VERSION 5.7 ;
  NOWIREEXTENSIONATPIN ON ;
  DIVIDERCHAR "/" ;
  BUSBITCHARS "[]" ;
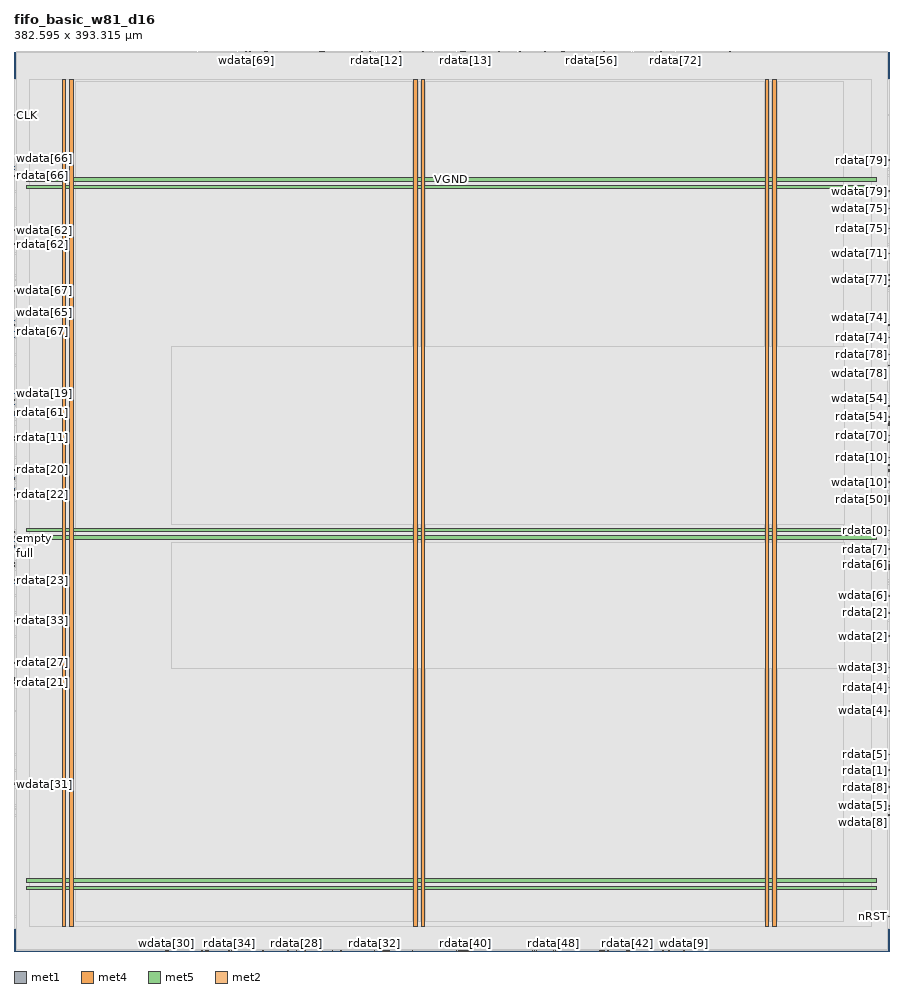
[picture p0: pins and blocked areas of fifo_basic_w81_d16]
MACRO fifo_basic_w81_d16
  CLASS BLOCK ;
  FOREIGN fifo_basic_w81_d16 ;
  ORIGIN 0.000 0.000 ;
  SIZE 382.595 BY 393.315 ;
  PIN CLK
    DIRECTION INPUT ;
    USE SIGNAL ;
    ANTENNAGATEAREA 0.852000 ;
    PORT
      LAYER met1 ;
        RECT 0.000 365.190 0.300 365.470 ;
    END
  END CLK
  PIN VGND
    DIRECTION INOUT ;
    USE GROUND ;
    PORT
      LAYER met4 ;
        RECT 24.340 10.640 25.940 381.040 ;
    END
    PORT
      LAYER met4 ;
        RECT 177.940 10.640 179.540 381.040 ;
    END
    PORT
      LAYER met4 ;
        RECT 331.540 10.640 333.140 381.040 ;
    END
    PORT
      LAYER met5 ;
        RECT 5.520 30.030 376.740 31.630 ;
    END
    PORT
      LAYER met5 ;
        RECT 5.520 183.210 376.740 184.810 ;
    END
    PORT
      LAYER met5 ;
        RECT 5.520 336.390 376.740 337.990 ;
    END
  END VGND
  PIN VPWR
    DIRECTION INOUT ;
    USE POWER ;
    PORT
      LAYER met4 ;
        RECT 21.040 10.640 22.640 381.040 ;
    END
    PORT
      LAYER met4 ;
        RECT 174.640 10.640 176.240 381.040 ;
    END
    PORT
      LAYER met4 ;
        RECT 328.240 10.640 329.840 381.040 ;
    END
    PORT
      LAYER met5 ;
        RECT 5.520 26.730 376.740 28.330 ;
    END
    PORT
      LAYER met5 ;
        RECT 5.520 179.910 376.740 181.510 ;
    END
    PORT
      LAYER met5 ;
        RECT 5.520 333.090 376.740 334.690 ;
    END
  END VPWR
  PIN empty
    DIRECTION OUTPUT ;
    USE SIGNAL ;
    ANTENNADIFFAREA 0.702900 ;
    PORT
      LAYER met1 ;
        RECT 0.000 180.230 0.300 180.510 ;
    END
  END empty
  PIN full
    DIRECTION OUTPUT ;
    USE SIGNAL ;
    ANTENNADIFFAREA 0.702900 ;
    PORT
      LAYER met1 ;
        RECT 0.000 176.830 0.300 177.110 ;
    END
  END full
  PIN nRST
    DIRECTION INPUT ;
    USE SIGNAL ;
    ANTENNAGATEAREA 0.196500 ;
    PORT
      LAYER met1 ;
        RECT 382.295 14.990 382.595 15.270 ;
    END
  END nRST
  PIN rdata[0]
    DIRECTION OUTPUT ;
    USE SIGNAL ;
    ANTENNADIFFAREA 0.702900 ;
    PORT
      LAYER met1 ;
        RECT 382.295 183.630 382.595 183.910 ;
    END
  END rdata[0]
  PIN rdata[10]
    DIRECTION OUTPUT ;
    USE SIGNAL ;
    ANTENNADIFFAREA 0.702900 ;
    PORT
      LAYER met1 ;
        RECT 382.295 215.590 382.595 215.870 ;
    END
  END rdata[10]
  PIN rdata[11]
    DIRECTION OUTPUT ;
    USE SIGNAL ;
    ANTENNADIFFAREA 0.702900 ;
    PORT
      LAYER met1 ;
        RECT 0.000 224.430 0.300 224.710 ;
    END
  END rdata[11]
  PIN rdata[12]
    DIRECTION OUTPUT ;
    USE SIGNAL ;
    ANTENNADIFFAREA 0.702900 ;
    PORT
      LAYER met2 ;
        RECT 158.330 393.035 158.610 393.315 ;
    END
  END rdata[12]
  PIN rdata[13]
    DIRECTION OUTPUT ;
    USE SIGNAL ;
    ANTENNADIFFAREA 0.702900 ;
    PORT
      LAYER met2 ;
        RECT 196.970 393.035 197.250 393.315 ;
    END
  END rdata[13]
  PIN rdata[14]
    DIRECTION OUTPUT ;
    USE SIGNAL ;
    ANTENNADIFFAREA 0.702900 ;
    PORT
      LAYER met2 ;
        RECT 193.290 393.035 193.570 393.315 ;
    END
  END rdata[14]
  PIN rdata[15]
    DIRECTION OUTPUT ;
    USE SIGNAL ;
    ANTENNADIFFAREA 0.702900 ;
    PORT
      LAYER met2 ;
        RECT 135.330 393.035 135.610 393.315 ;
    END
  END rdata[15]
  PIN rdata[16]
    DIRECTION OUTPUT ;
    USE SIGNAL ;
    ANTENNADIFFAREA 0.702900 ;
    PORT
      LAYER met2 ;
        RECT 134.410 393.035 134.690 393.315 ;
    END
  END rdata[16]
  PIN rdata[17]
    DIRECTION OUTPUT ;
    USE SIGNAL ;
    ANTENNADIFFAREA 0.702900 ;
    PORT
      LAYER met2 ;
        RECT 151.890 393.035 152.170 393.315 ;
    END
  END rdata[17]
  PIN rdata[18]
    DIRECTION OUTPUT ;
    USE SIGNAL ;
    ANTENNADIFFAREA 0.702900 ;
    PORT
      LAYER met2 ;
        RECT 178.570 393.035 178.850 393.315 ;
    END
  END rdata[18]
  PIN rdata[19]
    DIRECTION OUTPUT ;
    USE SIGNAL ;
    ANTENNADIFFAREA 0.702900 ;
    PORT
      LAYER met1 ;
        RECT 0.000 223.070 0.300 223.350 ;
    END
  END rdata[19]
  PIN rdata[1]
    DIRECTION OUTPUT ;
    USE SIGNAL ;
    ANTENNADIFFAREA 0.702900 ;
    PORT
      LAYER met1 ;
        RECT 382.295 78.910 382.595 79.190 ;
    END
  END rdata[1]
  PIN rdata[20]
    DIRECTION OUTPUT ;
    USE SIGNAL ;
    ANTENNADIFFAREA 0.702900 ;
    PORT
      LAYER met1 ;
        RECT 0.000 210.150 0.300 210.430 ;
    END
  END rdata[20]
  PIN rdata[21]
    DIRECTION OUTPUT ;
    USE SIGNAL ;
    ANTENNADIFFAREA 0.702900 ;
    PORT
      LAYER met1 ;
        RECT 0.000 116.990 0.300 117.270 ;
    END
  END rdata[21]
  PIN rdata[22]
    DIRECTION OUTPUT ;
    USE SIGNAL ;
    ANTENNADIFFAREA 0.702900 ;
    PORT
      LAYER met1 ;
        RECT 0.000 199.270 0.300 199.550 ;
    END
  END rdata[22]
  PIN rdata[23]
    DIRECTION OUTPUT ;
    USE SIGNAL ;
    ANTENNADIFFAREA 0.702900 ;
    PORT
      LAYER met1 ;
        RECT 0.000 161.870 0.300 162.150 ;
    END
  END rdata[23]
  PIN rdata[24]
    DIRECTION OUTPUT ;
    USE SIGNAL ;
    ANTENNADIFFAREA 0.702900 ;
    PORT
      LAYER met2 ;
        RECT 83.810 0.000 84.090 0.280 ;
    END
  END rdata[24]
  PIN rdata[25]
    DIRECTION OUTPUT ;
    USE SIGNAL ;
    ANTENNADIFFAREA 0.702900 ;
    PORT
      LAYER met1 ;
        RECT 0.000 169.350 0.300 169.630 ;
    END
  END rdata[25]
  PIN rdata[26]
    DIRECTION OUTPUT ;
    USE SIGNAL ;
    ANTENNADIFFAREA 0.702900 ;
    PORT
      LAYER met1 ;
        RECT 0.000 201.990 0.300 202.270 ;
    END
  END rdata[26]
  PIN rdata[27]
    DIRECTION OUTPUT ;
    USE SIGNAL ;
    ANTENNADIFFAREA 0.702900 ;
    PORT
      LAYER met1 ;
        RECT 0.000 125.830 0.300 126.110 ;
    END
  END rdata[27]
  PIN rdata[28]
    DIRECTION OUTPUT ;
    USE SIGNAL ;
    ANTENNADIFFAREA 0.702900 ;
    PORT
      LAYER met2 ;
        RECT 123.370 0.000 123.650 0.280 ;
    END
  END rdata[28]
  PIN rdata[29]
    DIRECTION OUTPUT ;
    USE SIGNAL ;
    ANTENNADIFFAREA 0.702900 ;
    PORT
      LAYER met1 ;
        RECT 0.000 178.870 0.300 179.150 ;
    END
  END rdata[29]
  PIN rdata[2]
    DIRECTION OUTPUT ;
    USE SIGNAL ;
    ANTENNADIFFAREA 0.702900 ;
    PORT
      LAYER met1 ;
        RECT 382.295 147.590 382.595 147.870 ;
    END
  END rdata[2]
  PIN rdata[30]
    DIRECTION OUTPUT ;
    USE SIGNAL ;
    ANTENNADIFFAREA 0.702900 ;
    PORT
      LAYER met2 ;
        RECT 84.730 0.000 85.010 0.280 ;
    END
  END rdata[30]
  PIN rdata[31]
    DIRECTION OUTPUT ;
    USE SIGNAL ;
    ANTENNADIFFAREA 0.702900 ;
    PORT
      LAYER met1 ;
        RECT 0.000 73.470 0.300 73.750 ;
    END
  END rdata[31]
  PIN rdata[32]
    DIRECTION OUTPUT ;
    USE SIGNAL ;
    ANTENNADIFFAREA 0.702900 ;
    PORT
      LAYER met2 ;
        RECT 157.410 0.000 157.690 0.280 ;
    END
  END rdata[32]
  PIN rdata[33]
    DIRECTION OUTPUT ;
    USE SIGNAL ;
    ANTENNADIFFAREA 0.702900 ;
    PORT
      LAYER met1 ;
        RECT 0.000 144.190 0.300 144.470 ;
    END
  END rdata[33]
  PIN rdata[34]
    DIRECTION OUTPUT ;
    USE SIGNAL ;
    ANTENNADIFFAREA 0.702900 ;
    PORT
      LAYER met2 ;
        RECT 93.930 0.000 94.210 0.280 ;
    END
  END rdata[34]
  PIN rdata[35]
    DIRECTION OUTPUT ;
    USE SIGNAL ;
    ANTENNADIFFAREA 0.702900 ;
    PORT
      LAYER met2 ;
        RECT 142.690 0.000 142.970 0.280 ;
    END
  END rdata[35]
  PIN rdata[36]
    DIRECTION OUTPUT ;
    USE SIGNAL ;
    ANTENNADIFFAREA 0.702900 ;
    PORT
      LAYER met2 ;
        RECT 127.050 0.000 127.330 0.280 ;
    END
  END rdata[36]
  PIN rdata[37]
    DIRECTION OUTPUT ;
    USE SIGNAL ;
    ANTENNADIFFAREA 0.702900 ;
    PORT
      LAYER met2 ;
        RECT 108.650 0.000 108.930 0.280 ;
    END
  END rdata[37]
  PIN rdata[38]
    DIRECTION OUTPUT ;
    USE SIGNAL ;
    ANTENNADIFFAREA 0.702900 ;
    PORT
      LAYER met2 ;
        RECT 161.090 0.000 161.370 0.280 ;
    END
  END rdata[38]
  PIN rdata[39]
    DIRECTION OUTPUT ;
    USE SIGNAL ;
    ANTENNADIFFAREA 0.702900 ;
    PORT
      LAYER met2 ;
        RECT 173.970 0.000 174.250 0.280 ;
    END
  END rdata[39]
  PIN rdata[3]
    DIRECTION OUTPUT ;
    USE SIGNAL ;
    ANTENNADIFFAREA 0.702900 ;
    PORT
      LAYER met2 ;
        RECT 283.450 0.000 283.730 0.280 ;
    END
  END rdata[3]
  PIN rdata[40]
    DIRECTION OUTPUT ;
    USE SIGNAL ;
    ANTENNADIFFAREA 0.702900 ;
    PORT
      LAYER met2 ;
        RECT 196.970 0.000 197.250 0.280 ;
    END
  END rdata[40]
  PIN rdata[41]
    DIRECTION OUTPUT ;
    USE SIGNAL ;
    ANTENNADIFFAREA 0.702900 ;
    PORT
      LAYER met2 ;
        RECT 193.290 0.000 193.570 0.280 ;
    END
  END rdata[41]
  PIN rdata[42]
    DIRECTION OUTPUT ;
    USE SIGNAL ;
    ANTENNADIFFAREA 0.702900 ;
    PORT
      LAYER met2 ;
        RECT 267.810 0.000 268.090 0.280 ;
    END
  END rdata[42]
  PIN rdata[43]
    DIRECTION OUTPUT ;
    USE SIGNAL ;
    ANTENNADIFFAREA 0.702900 ;
    PORT
      LAYER met2 ;
        RECT 237.450 0.000 237.730 0.280 ;
    END
  END rdata[43]
  PIN rdata[44]
    DIRECTION OUTPUT ;
    USE SIGNAL ;
    ANTENNADIFFAREA 0.702900 ;
    PORT
      LAYER met2 ;
        RECT 199.730 0.000 200.010 0.280 ;
    END
  END rdata[44]
  PIN rdata[45]
    DIRECTION OUTPUT ;
    USE SIGNAL ;
    ANTENNADIFFAREA 0.702900 ;
    PORT
      LAYER met2 ;
        RECT 259.530 0.000 259.810 0.280 ;
    END
  END rdata[45]
  PIN rdata[46]
    DIRECTION OUTPUT ;
    USE SIGNAL ;
    ANTENNADIFFAREA 0.702900 ;
    PORT
      LAYER met2 ;
        RECT 195.130 0.000 195.410 0.280 ;
    END
  END rdata[46]
  PIN rdata[47]
    DIRECTION OUTPUT ;
    USE SIGNAL ;
    ANTENNADIFFAREA 0.702900 ;
    PORT
      LAYER met2 ;
        RECT 226.410 0.000 226.690 0.280 ;
    END
  END rdata[47]
  PIN rdata[48]
    DIRECTION OUTPUT ;
    USE SIGNAL ;
    ANTENNADIFFAREA 0.702900 ;
    PORT
      LAYER met2 ;
        RECT 235.610 0.000 235.890 0.280 ;
    END
  END rdata[48]
  PIN rdata[49]
    DIRECTION OUTPUT ;
    USE SIGNAL ;
    ANTENNADIFFAREA 0.702900 ;
    PORT
      LAYER met2 ;
        RECT 268.730 0.000 269.010 0.280 ;
    END
  END rdata[49]
  PIN rdata[4]
    DIRECTION OUTPUT ;
    USE SIGNAL ;
    ANTENNADIFFAREA 0.702900 ;
    PORT
      LAYER met1 ;
        RECT 382.295 114.950 382.595 115.230 ;
    END
  END rdata[4]
  PIN rdata[50]
    DIRECTION OUTPUT ;
    USE SIGNAL ;
    ANTENNADIFFAREA 0.702900 ;
    PORT
      LAYER met1 ;
        RECT 382.295 197.230 382.595 197.510 ;
    END
  END rdata[50]
  PIN rdata[51]
    DIRECTION OUTPUT ;
    USE SIGNAL ;
    ANTENNADIFFAREA 0.702900 ;
    PORT
      LAYER met1 ;
        RECT 382.295 196.550 382.595 196.830 ;
    END
  END rdata[51]
  PIN rdata[52]
    DIRECTION OUTPUT ;
    USE SIGNAL ;
    ANTENNADIFFAREA 0.702900 ;
    PORT
      LAYER met2 ;
        RECT 219.970 393.035 220.250 393.315 ;
    END
  END rdata[52]
  PIN rdata[53]
    DIRECTION OUTPUT ;
    USE SIGNAL ;
    ANTENNADIFFAREA 0.702900 ;
    PORT
      LAYER met2 ;
        RECT 269.650 393.035 269.930 393.315 ;
    END
  END rdata[53]
  PIN rdata[54]
    DIRECTION OUTPUT ;
    USE SIGNAL ;
    ANTENNADIFFAREA 0.702900 ;
    PORT
      LAYER met1 ;
        RECT 382.295 233.270 382.595 233.550 ;
    END
  END rdata[54]
  PIN rdata[55]
    DIRECTION OUTPUT ;
    USE SIGNAL ;
    ANTENNADIFFAREA 0.702900 ;
    PORT
      LAYER met2 ;
        RECT 270.570 393.035 270.850 393.315 ;
    END
  END rdata[55]
  PIN rdata[56]
    DIRECTION OUTPUT ;
    USE SIGNAL ;
    ANTENNADIFFAREA 0.702900 ;
    PORT
      LAYER met2 ;
        RECT 252.170 393.035 252.450 393.315 ;
    END
  END rdata[56]
  PIN rdata[57]
    DIRECTION OUTPUT ;
    USE SIGNAL ;
    ANTENNADIFFAREA 0.702900 ;
    PORT
      LAYER met2 ;
        RECT 231.930 393.035 232.210 393.315 ;
    END
  END rdata[57]
  PIN rdata[58]
    DIRECTION OUTPUT ;
    USE SIGNAL ;
    ANTENNADIFFAREA 0.702900 ;
    PORT
      LAYER met1 ;
        RECT 382.295 231.230 382.595 231.510 ;
    END
  END rdata[58]
  PIN rdata[59]
    DIRECTION OUTPUT ;
    USE SIGNAL ;
    ANTENNADIFFAREA 0.702900 ;
    PORT
      LAYER met2 ;
        RECT 211.690 393.035 211.970 393.315 ;
    END
  END rdata[59]
  PIN rdata[5]
    DIRECTION OUTPUT ;
    USE SIGNAL ;
    ANTENNADIFFAREA 0.702900 ;
    PORT
      LAYER met1 ;
        RECT 382.295 85.710 382.595 85.990 ;
    END
  END rdata[5]
  PIN rdata[60]
    DIRECTION OUTPUT ;
    USE SIGNAL ;
    ANTENNADIFFAREA 0.702900 ;
    PORT
      LAYER met2 ;
        RECT 109.570 393.035 109.850 393.315 ;
    END
  END rdata[60]
  PIN rdata[61]
    DIRECTION OUTPUT ;
    USE SIGNAL ;
    ANTENNADIFFAREA 0.702900 ;
    PORT
      LAYER met1 ;
        RECT 0.000 235.310 0.300 235.590 ;
    END
  END rdata[61]
  PIN rdata[62]
    DIRECTION OUTPUT ;
    USE SIGNAL ;
    ANTENNADIFFAREA 0.702900 ;
    PORT
      LAYER met1 ;
        RECT 0.000 308.750 0.300 309.030 ;
    END
  END rdata[62]
  PIN rdata[63]
    DIRECTION OUTPUT ;
    USE SIGNAL ;
    ANTENNADIFFAREA 0.702900 ;
    PORT
      LAYER met2 ;
        RECT 97.610 393.035 97.890 393.315 ;
    END
  END rdata[63]
  PIN rdata[64]
    DIRECTION OUTPUT ;
    USE SIGNAL ;
    ANTENNADIFFAREA 0.702900 ;
    PORT
      LAYER met2 ;
        RECT 80.130 393.035 80.410 393.315 ;
    END
  END rdata[64]
  PIN rdata[65]
    DIRECTION OUTPUT ;
    USE SIGNAL ;
    ANTENNADIFFAREA 0.702900 ;
    PORT
      LAYER met1 ;
        RECT 0.000 273.390 0.300 273.670 ;
    END
  END rdata[65]
  PIN rdata[66]
    DIRECTION OUTPUT ;
    USE SIGNAL ;
    ANTENNADIFFAREA 0.702900 ;
    PORT
      LAYER met1 ;
        RECT 0.000 338.670 0.300 338.950 ;
    END
  END rdata[66]
  PIN rdata[67]
    DIRECTION OUTPUT ;
    USE SIGNAL ;
    ANTENNADIFFAREA 0.702900 ;
    PORT
      LAYER met1 ;
        RECT 0.000 270.670 0.300 270.950 ;
    END
  END rdata[67]
  PIN rdata[68]
    DIRECTION OUTPUT ;
    USE SIGNAL ;
    ANTENNADIFFAREA 0.702900 ;
    PORT
      LAYER met1 ;
        RECT 0.000 234.630 0.300 234.910 ;
    END
  END rdata[68]
  PIN rdata[69]
    DIRECTION OUTPUT ;
    USE SIGNAL ;
    ANTENNADIFFAREA 0.702900 ;
    PORT
      LAYER met2 ;
        RECT 110.490 393.035 110.770 393.315 ;
    END
  END rdata[69]
  PIN rdata[6]
    DIRECTION OUTPUT ;
    USE SIGNAL ;
    ANTENNADIFFAREA 0.702900 ;
    PORT
      LAYER met1 ;
        RECT 382.295 168.670 382.595 168.950 ;
    END
  END rdata[6]
  PIN rdata[70]
    DIRECTION OUTPUT ;
    USE SIGNAL ;
    ANTENNADIFFAREA 0.702900 ;
    PORT
      LAYER met1 ;
        RECT 382.295 225.110 382.595 225.390 ;
    END
  END rdata[70]
  PIN rdata[71]
    DIRECTION OUTPUT ;
    USE SIGNAL ;
    ANTENNADIFFAREA 0.702900 ;
    PORT
      LAYER met1 ;
        RECT 382.295 295.150 382.595 295.430 ;
    END
  END rdata[71]
  PIN rdata[72]
    DIRECTION OUTPUT ;
    USE SIGNAL ;
    ANTENNADIFFAREA 0.702900 ;
    PORT
      LAYER met2 ;
        RECT 288.970 393.035 289.250 393.315 ;
    END
  END rdata[72]
  PIN rdata[73]
    DIRECTION OUTPUT ;
    USE SIGNAL ;
    ANTENNADIFFAREA 0.702900 ;
    PORT
      LAYER met1 ;
        RECT 382.295 222.390 382.595 222.670 ;
    END
  END rdata[73]
  PIN rdata[74]
    DIRECTION OUTPUT ;
    USE SIGNAL ;
    ANTENNADIFFAREA 0.702900 ;
    PORT
      LAYER met1 ;
        RECT 382.295 267.950 382.595 268.230 ;
    END
  END rdata[74]
  PIN rdata[75]
    DIRECTION OUTPUT ;
    USE SIGNAL ;
    ANTENNADIFFAREA 0.702900 ;
    PORT
      LAYER met1 ;
        RECT 382.295 315.550 382.595 315.830 ;
    END
  END rdata[75]
  PIN rdata[76]
    DIRECTION OUTPUT ;
    USE SIGNAL ;
    ANTENNADIFFAREA 0.702900 ;
    PORT
      LAYER met1 ;
        RECT 382.295 229.870 382.595 230.150 ;
    END
  END rdata[76]
  PIN rdata[77]
    DIRECTION OUTPUT ;
    USE SIGNAL ;
    ANTENNADIFFAREA 0.702900 ;
    PORT
      LAYER met1 ;
        RECT 382.295 290.390 382.595 290.670 ;
    END
  END rdata[77]
  PIN rdata[78]
    DIRECTION OUTPUT ;
    USE SIGNAL ;
    ANTENNADIFFAREA 0.702900 ;
    PORT
      LAYER met1 ;
        RECT 382.295 260.470 382.595 260.750 ;
    END
  END rdata[78]
  PIN rdata[79]
    DIRECTION OUTPUT ;
    USE SIGNAL ;
    ANTENNADIFFAREA 0.702900 ;
    PORT
      LAYER met1 ;
        RECT 382.295 345.470 382.595 345.750 ;
    END
  END rdata[79]
  PIN rdata[7]
    DIRECTION OUTPUT ;
    USE SIGNAL ;
    ANTENNADIFFAREA 0.702900 ;
    PORT
      LAYER met1 ;
        RECT 382.295 175.470 382.595 175.750 ;
    END
  END rdata[7]
  PIN rdata[80]
    DIRECTION OUTPUT ;
    USE SIGNAL ;
    ANTENNADIFFAREA 0.702900 ;
    PORT
      LAYER met1 ;
        RECT 382.295 170.030 382.595 170.310 ;
    END
  END rdata[80]
  PIN rdata[8]
    DIRECTION OUTPUT ;
    USE SIGNAL ;
    ANTENNADIFFAREA 0.702900 ;
    PORT
      LAYER met1 ;
        RECT 382.295 71.430 382.595 71.710 ;
    END
  END rdata[8]
  PIN rdata[9]
    DIRECTION OUTPUT ;
    USE SIGNAL ;
    ANTENNADIFFAREA 0.702900 ;
    PORT
      LAYER met2 ;
        RECT 286.210 0.000 286.490 0.280 ;
    END
  END rdata[9]
  PIN ren
    DIRECTION INPUT ;
    USE SIGNAL ;
    ANTENNAGATEAREA 0.213000 ;
    PORT
      LAYER met1 ;
        RECT 0.000 180.910 0.300 181.190 ;
    END
  END ren
  PIN wdata[0]
    DIRECTION INPUT ;
    USE SIGNAL ;
    ANTENNAGATEAREA 0.213000 ;
    PORT
      LAYER met1 ;
        RECT 382.295 166.630 382.595 166.910 ;
    END
  END wdata[0]
  PIN wdata[10]
    DIRECTION INPUT ;
    USE SIGNAL ;
    ANTENNAGATEAREA 0.213000 ;
    PORT
      LAYER met1 ;
        RECT 382.295 204.710 382.595 204.990 ;
    END
  END wdata[10]
  PIN wdata[11]
    DIRECTION INPUT ;
    USE SIGNAL ;
    ANTENNAGATEAREA 0.213000 ;
    PORT
      LAYER met1 ;
        RECT 0.000 233.950 0.300 234.230 ;
    END
  END wdata[11]
  PIN wdata[12]
    DIRECTION INPUT ;
    USE SIGNAL ;
    ANTENNAGATEAREA 0.213000 ;
    PORT
      LAYER met2 ;
        RECT 155.570 393.035 155.850 393.315 ;
    END
  END wdata[12]
  PIN wdata[13]
    DIRECTION INPUT ;
    USE SIGNAL ;
    ANTENNAGATEAREA 0.213000 ;
    PORT
      LAYER met2 ;
        RECT 196.050 393.035 196.330 393.315 ;
    END
  END wdata[13]
  PIN wdata[14]
    DIRECTION INPUT ;
    USE SIGNAL ;
    ANTENNAGATEAREA 0.213000 ;
    PORT
      LAYER met2 ;
        RECT 195.130 393.035 195.410 393.315 ;
    END
  END wdata[14]
  PIN wdata[15]
    DIRECTION INPUT ;
    USE SIGNAL ;
    ANTENNAGATEAREA 0.213000 ;
    PORT
      LAYER met2 ;
        RECT 133.490 393.035 133.770 393.315 ;
    END
  END wdata[15]
  PIN wdata[16]
    DIRECTION INPUT ;
    USE SIGNAL ;
    ANTENNAGATEAREA 0.213000 ;
    PORT
      LAYER met2 ;
        RECT 157.410 393.035 157.690 393.315 ;
    END
  END wdata[16]
  PIN wdata[17]
    DIRECTION INPUT ;
    USE SIGNAL ;
    ANTENNAGATEAREA 0.213000 ;
    PORT
      LAYER met2 ;
        RECT 168.450 393.035 168.730 393.315 ;
    END
  END wdata[17]
  PIN wdata[18]
    DIRECTION INPUT ;
    USE SIGNAL ;
    ANTENNAGATEAREA 0.213000 ;
    PORT
      LAYER met2 ;
        RECT 183.170 393.035 183.450 393.315 ;
    END
  END wdata[18]
  PIN wdata[19]
    DIRECTION INPUT ;
    USE SIGNAL ;
    ANTENNAGATEAREA 0.213000 ;
    PORT
      LAYER met1 ;
        RECT 0.000 243.470 0.300 243.750 ;
    END
  END wdata[19]
  PIN wdata[1]
    DIRECTION INPUT ;
    USE SIGNAL ;
    ANTENNAGATEAREA 0.213000 ;
    PORT
      LAYER met1 ;
        RECT 382.295 61.910 382.595 62.190 ;
    END
  END wdata[1]
  PIN wdata[20]
    DIRECTION INPUT ;
    USE SIGNAL ;
    ANTENNAGATEAREA 0.213000 ;
    PORT
      LAYER met1 ;
        RECT 0.000 206.750 0.300 207.030 ;
    END
  END wdata[20]
  PIN wdata[21]
    DIRECTION INPUT ;
    USE SIGNAL ;
    ANTENNAGATEAREA 0.213000 ;
    PORT
      LAYER met1 ;
        RECT 0.000 119.030 0.300 119.310 ;
    END
  END wdata[21]
  PIN wdata[22]
    DIRECTION INPUT ;
    USE SIGNAL ;
    ANTENNAGATEAREA 0.213000 ;
    PORT
      LAYER met1 ;
        RECT 0.000 206.070 0.300 206.350 ;
    END
  END wdata[22]
  PIN wdata[23]
    DIRECTION INPUT ;
    USE SIGNAL ;
    ANTENNAGATEAREA 0.213000 ;
    PORT
      LAYER met1 ;
        RECT 0.000 160.510 0.300 160.790 ;
    END
  END wdata[23]
  PIN wdata[24]
    DIRECTION INPUT ;
    USE SIGNAL ;
    ANTENNAGATEAREA 0.213000 ;
    PORT
      LAYER met2 ;
        RECT 81.970 0.000 82.250 0.280 ;
    END
  END wdata[24]
  PIN wdata[25]
    DIRECTION INPUT ;
    USE SIGNAL ;
    ANTENNAGATEAREA 0.213000 ;
    PORT
      LAYER met1 ;
        RECT 0.000 167.990 0.300 168.270 ;
    END
  END wdata[25]
  PIN wdata[26]
    DIRECTION INPUT ;
    USE SIGNAL ;
    ANTENNAGATEAREA 0.213000 ;
    PORT
      LAYER met1 ;
        RECT 0.000 201.310 0.300 201.590 ;
    END
  END wdata[26]
  PIN wdata[27]
    DIRECTION INPUT ;
    USE SIGNAL ;
    ANTENNAGATEAREA 0.213000 ;
    PORT
      LAYER met1 ;
        RECT 0.000 118.350 0.300 118.630 ;
    END
  END wdata[27]
  PIN wdata[28]
    DIRECTION INPUT ;
    USE SIGNAL ;
    ANTENNAGATEAREA 0.213000 ;
    PORT
      LAYER met2 ;
        RECT 94.850 0.000 95.130 0.280 ;
    END
  END wdata[28]
  PIN wdata[29]
    DIRECTION INPUT ;
    USE SIGNAL ;
    ANTENNAGATEAREA 0.213000 ;
    PORT
      LAYER met1 ;
        RECT 0.000 182.950 0.300 183.230 ;
    END
  END wdata[29]
  PIN wdata[2]
    DIRECTION INPUT ;
    USE SIGNAL ;
    ANTENNAGATEAREA 0.213000 ;
    PORT
      LAYER met1 ;
        RECT 382.295 137.390 382.595 137.670 ;
    END
  END wdata[2]
  PIN wdata[30]
    DIRECTION INPUT ;
    USE SIGNAL ;
    ANTENNAGATEAREA 0.213000 ;
    PORT
      LAYER met2 ;
        RECT 66.330 0.000 66.610 0.280 ;
    END
  END wdata[30]
  PIN wdata[31]
    DIRECTION INPUT ;
    USE SIGNAL ;
    ANTENNAGATEAREA 0.213000 ;
    PORT
      LAYER met1 ;
        RECT 0.000 72.790 0.300 73.070 ;
    END
  END wdata[31]
  PIN wdata[32]
    DIRECTION INPUT ;
    USE SIGNAL ;
    ANTENNAGATEAREA 0.213000 ;
    PORT
      LAYER met2 ;
        RECT 162.010 0.000 162.290 0.280 ;
    END
  END wdata[32]
  PIN wdata[33]
    DIRECTION INPUT ;
    USE SIGNAL ;
    ANTENNAGATEAREA 0.213000 ;
    PORT
      LAYER met2 ;
        RECT 134.410 0.000 134.690 0.280 ;
    END
  END wdata[33]
  PIN wdata[34]
    DIRECTION INPUT ;
    USE SIGNAL ;
    ANTENNAGATEAREA 0.213000 ;
    PORT
      LAYER met2 ;
        RECT 67.250 0.000 67.530 0.280 ;
    END
  END wdata[34]
  PIN wdata[35]
    DIRECTION INPUT ;
    USE SIGNAL ;
    ANTENNAGATEAREA 0.213000 ;
    PORT
      LAYER met2 ;
        RECT 139.010 0.000 139.290 0.280 ;
    END
  END wdata[35]
  PIN wdata[36]
    DIRECTION INPUT ;
    USE SIGNAL ;
    ANTENNAGATEAREA 0.213000 ;
    PORT
      LAYER met2 ;
        RECT 119.690 0.000 119.970 0.280 ;
    END
  END wdata[36]
  PIN wdata[37]
    DIRECTION INPUT ;
    USE SIGNAL ;
    ANTENNAGATEAREA 0.213000 ;
    PORT
      LAYER met2 ;
        RECT 95.770 0.000 96.050 0.280 ;
    END
  END wdata[37]
  PIN wdata[38]
    DIRECTION INPUT ;
    USE SIGNAL ;
    ANTENNAGATEAREA 0.213000 ;
    PORT
      LAYER met2 ;
        RECT 162.930 0.000 163.210 0.280 ;
    END
  END wdata[38]
  PIN wdata[39]
    DIRECTION INPUT ;
    USE SIGNAL ;
    ANTENNAGATEAREA 0.213000 ;
    PORT
      LAYER met2 ;
        RECT 163.850 0.000 164.130 0.280 ;
    END
  END wdata[39]
  PIN wdata[3]
    DIRECTION INPUT ;
    USE SIGNAL ;
    ANTENNAGATEAREA 0.213000 ;
    PORT
      LAYER met1 ;
        RECT 382.295 123.790 382.595 124.070 ;
    END
  END wdata[3]
  PIN wdata[40]
    DIRECTION INPUT ;
    USE SIGNAL ;
    ANTENNAGATEAREA 0.213000 ;
    PORT
      LAYER met2 ;
        RECT 194.210 0.000 194.490 0.280 ;
    END
  END wdata[40]
  PIN wdata[41]
    DIRECTION INPUT ;
    USE SIGNAL ;
    ANTENNAGATEAREA 0.213000 ;
    PORT
      LAYER met2 ;
        RECT 196.050 0.000 196.330 0.280 ;
    END
  END wdata[41]
  PIN wdata[42]
    DIRECTION INPUT ;
    USE SIGNAL ;
    ANTENNAGATEAREA 0.213000 ;
    PORT
      LAYER met2 ;
        RECT 256.770 0.000 257.050 0.280 ;
    END
  END wdata[42]
  PIN wdata[43]
    DIRECTION INPUT ;
    USE SIGNAL ;
    ANTENNAGATEAREA 0.213000 ;
    PORT
      LAYER met2 ;
        RECT 228.250 0.000 228.530 0.280 ;
    END
  END wdata[43]
  PIN wdata[44]
    DIRECTION INPUT ;
    USE SIGNAL ;
    ANTENNAGATEAREA 0.213000 ;
    PORT
      LAYER met2 ;
        RECT 197.890 0.000 198.170 0.280 ;
    END
  END wdata[44]
  PIN wdata[45]
    DIRECTION INPUT ;
    USE SIGNAL ;
    ANTENNAGATEAREA 0.213000 ;
    PORT
      LAYER met2 ;
        RECT 255.850 0.000 256.130 0.280 ;
    END
  END wdata[45]
  PIN wdata[46]
    DIRECTION INPUT ;
    USE SIGNAL ;
    ANTENNAGATEAREA 0.213000 ;
    PORT
      LAYER met2 ;
        RECT 198.810 0.000 199.090 0.280 ;
    END
  END wdata[46]
  PIN wdata[47]
    DIRECTION INPUT ;
    USE SIGNAL ;
    ANTENNAGATEAREA 0.213000 ;
    PORT
      LAYER met2 ;
        RECT 227.330 0.000 227.610 0.280 ;
    END
  END wdata[47]
  PIN wdata[48]
    DIRECTION INPUT ;
    USE SIGNAL ;
    ANTENNAGATEAREA 0.213000 ;
    PORT
      LAYER met2 ;
        RECT 236.530 0.000 236.810 0.280 ;
    END
  END wdata[48]
  PIN wdata[49]
    DIRECTION INPUT ;
    USE SIGNAL ;
    ANTENNAGATEAREA 0.213000 ;
    PORT
      LAYER met2 ;
        RECT 257.690 0.000 257.970 0.280 ;
    END
  END wdata[49]
  PIN wdata[4]
    DIRECTION INPUT ;
    USE SIGNAL ;
    ANTENNAGATEAREA 0.213000 ;
    PORT
      LAYER met1 ;
        RECT 382.295 104.750 382.595 105.030 ;
    END
  END wdata[4]
  PIN wdata[50]
    DIRECTION INPUT ;
    USE SIGNAL ;
    ANTENNAGATEAREA 0.213000 ;
    PORT
      LAYER met1 ;
        RECT 382.295 198.590 382.595 198.870 ;
    END
  END wdata[50]
  PIN wdata[51]
    DIRECTION INPUT ;
    USE SIGNAL ;
    ANTENNAGATEAREA 0.213000 ;
    PORT
      LAYER met1 ;
        RECT 382.295 197.910 382.595 198.190 ;
    END
  END wdata[51]
  PIN wdata[52]
    DIRECTION INPUT ;
    USE SIGNAL ;
    ANTENNAGATEAREA 0.213000 ;
    PORT
      LAYER met2 ;
        RECT 240.210 393.035 240.490 393.315 ;
    END
  END wdata[52]
  PIN wdata[53]
    DIRECTION INPUT ;
    USE SIGNAL ;
    ANTENNAGATEAREA 0.213000 ;
    PORT
      LAYER met2 ;
        RECT 282.530 393.035 282.810 393.315 ;
    END
  END wdata[53]
  PIN wdata[54]
    DIRECTION INPUT ;
    USE SIGNAL ;
    ANTENNAGATEAREA 0.213000 ;
    PORT
      LAYER met1 ;
        RECT 382.295 238.030 382.595 238.310 ;
    END
  END wdata[54]
  PIN wdata[55]
    DIRECTION INPUT ;
    USE SIGNAL ;
    ANTENNAGATEAREA 0.213000 ;
    PORT
      LAYER met2 ;
        RECT 279.770 393.035 280.050 393.315 ;
    END
  END wdata[55]
  PIN wdata[56]
    DIRECTION INPUT ;
    USE SIGNAL ;
    ANTENNAGATEAREA 0.213000 ;
    PORT
      LAYER met2 ;
        RECT 257.690 393.035 257.970 393.315 ;
    END
  END wdata[56]
  PIN wdata[57]
    DIRECTION INPUT ;
    USE SIGNAL ;
    ANTENNAGATEAREA 0.213000 ;
    PORT
      LAYER met2 ;
        RECT 239.290 393.035 239.570 393.315 ;
    END
  END wdata[57]
  PIN wdata[58]
    DIRECTION INPUT ;
    USE SIGNAL ;
    ANTENNAGATEAREA 0.213000 ;
    PORT
      LAYER met1 ;
        RECT 382.295 230.550 382.595 230.830 ;
    END
  END wdata[58]
  PIN wdata[59]
    DIRECTION INPUT ;
    USE SIGNAL ;
    ANTENNAGATEAREA 0.213000 ;
    PORT
      LAYER met2 ;
        RECT 220.890 393.035 221.170 393.315 ;
    END
  END wdata[59]
  PIN wdata[5]
    DIRECTION INPUT ;
    USE SIGNAL ;
    ANTENNAGATEAREA 0.213000 ;
    PORT
      LAYER met1 ;
        RECT 382.295 63.270 382.595 63.550 ;
    END
  END wdata[5]
  PIN wdata[60]
    DIRECTION INPUT ;
    USE SIGNAL ;
    ANTENNAGATEAREA 0.213000 ;
    PORT
      LAYER met2 ;
        RECT 103.130 393.035 103.410 393.315 ;
    END
  END wdata[60]
  PIN wdata[61]
    DIRECTION INPUT ;
    USE SIGNAL ;
    ANTENNAGATEAREA 0.213000 ;
    PORT
      LAYER met1 ;
        RECT 0.000 238.710 0.300 238.990 ;
    END
  END wdata[61]
  PIN wdata[62]
    DIRECTION INPUT ;
    USE SIGNAL ;
    ANTENNAGATEAREA 0.213000 ;
    PORT
      LAYER met1 ;
        RECT 0.000 314.870 0.300 315.150 ;
    END
  END wdata[62]
  PIN wdata[63]
    DIRECTION INPUT ;
    USE SIGNAL ;
    ANTENNAGATEAREA 0.213000 ;
    PORT
      LAYER met1 ;
        RECT 0.000 267.950 0.300 268.230 ;
    END
  END wdata[63]
  PIN wdata[64]
    DIRECTION INPUT ;
    USE SIGNAL ;
    ANTENNAGATEAREA 0.213000 ;
    PORT
      LAYER met1 ;
        RECT 0.000 341.390 0.300 341.670 ;
    END
  END wdata[64]
  PIN wdata[65]
    DIRECTION INPUT ;
    USE SIGNAL ;
    ANTENNAGATEAREA 0.213000 ;
    PORT
      LAYER met1 ;
        RECT 0.000 275.430 0.300 275.710 ;
    END
  END wdata[65]
  PIN wdata[66]
    DIRECTION INPUT ;
    USE SIGNAL ;
    ANTENNAGATEAREA 0.213000 ;
    PORT
      LAYER met1 ;
        RECT 0.000 342.750 0.300 343.030 ;
    END
  END wdata[66]
  PIN wdata[67]
    DIRECTION INPUT ;
    USE SIGNAL ;
    ANTENNAGATEAREA 0.213000 ;
    PORT
      LAYER met1 ;
        RECT 0.000 288.350 0.300 288.630 ;
    END
  END wdata[67]
  PIN wdata[68]
    DIRECTION INPUT ;
    USE SIGNAL ;
    ANTENNAGATEAREA 0.213000 ;
    PORT
      LAYER met1 ;
        RECT 0.000 240.750 0.300 241.030 ;
    END
  END wdata[68]
  PIN wdata[69]
    DIRECTION INPUT ;
    USE SIGNAL ;
    ANTENNAGATEAREA 0.213000 ;
    PORT
      LAYER met2 ;
        RECT 101.290 393.035 101.570 393.315 ;
    END
  END wdata[69]
  PIN wdata[6]
    DIRECTION INPUT ;
    USE SIGNAL ;
    ANTENNAGATEAREA 0.213000 ;
    PORT
      LAYER met1 ;
        RECT 382.295 155.070 382.595 155.350 ;
    END
  END wdata[6]
  PIN wdata[70]
    DIRECTION INPUT ;
    USE SIGNAL ;
    ANTENNAGATEAREA 0.213000 ;
    PORT
      LAYER met1 ;
        RECT 382.295 210.150 382.595 210.430 ;
    END
  END wdata[70]
  PIN wdata[71]
    DIRECTION INPUT ;
    USE SIGNAL ;
    ANTENNAGATEAREA 0.213000 ;
    PORT
      LAYER met1 ;
        RECT 382.295 304.670 382.595 304.950 ;
    END
  END wdata[71]
  PIN wdata[72]
    DIRECTION INPUT ;
    USE SIGNAL ;
    ANTENNAGATEAREA 0.213000 ;
    PORT
      LAYER met2 ;
        RECT 312.890 393.035 313.170 393.315 ;
    END
  END wdata[72]
  PIN wdata[73]
    DIRECTION INPUT ;
    USE SIGNAL ;
    ANTENNAGATEAREA 0.213000 ;
    PORT
      LAYER met1 ;
        RECT 382.295 209.470 382.595 209.750 ;
    END
  END wdata[73]
  PIN wdata[74]
    DIRECTION INPUT ;
    USE SIGNAL ;
    ANTENNAGATEAREA 0.213000 ;
    PORT
      LAYER met1 ;
        RECT 382.295 273.390 382.595 273.670 ;
    END
  END wdata[74]
  PIN wdata[75]
    DIRECTION INPUT ;
    USE SIGNAL ;
    ANTENNAGATEAREA 0.213000 ;
    PORT
      LAYER met1 ;
        RECT 382.295 324.390 382.595 324.670 ;
    END
  END wdata[75]
  PIN wdata[76]
    DIRECTION INPUT ;
    USE SIGNAL ;
    ANTENNAGATEAREA 0.213000 ;
    PORT
      LAYER met1 ;
        RECT 382.295 212.190 382.595 212.470 ;
    END
  END wdata[76]
  PIN wdata[77]
    DIRECTION INPUT ;
    USE SIGNAL ;
    ANTENNAGATEAREA 0.213000 ;
    PORT
      LAYER met1 ;
        RECT 382.295 293.110 382.595 293.390 ;
    END
  END wdata[77]
  PIN wdata[78]
    DIRECTION INPUT ;
    USE SIGNAL ;
    ANTENNAGATEAREA 0.213000 ;
    PORT
      LAYER met1 ;
        RECT 382.295 255.710 382.595 255.990 ;
    END
  END wdata[78]
  PIN wdata[79]
    DIRECTION INPUT ;
    USE SIGNAL ;
    ANTENNAGATEAREA 0.213000 ;
    PORT
      LAYER met1 ;
        RECT 382.295 331.870 382.595 332.150 ;
    END
  END wdata[79]
  PIN wdata[7]
    DIRECTION INPUT ;
    USE SIGNAL ;
    ANTENNAGATEAREA 0.213000 ;
    PORT
      LAYER met1 ;
        RECT 382.295 167.310 382.595 167.590 ;
    END
  END wdata[7]
  PIN wdata[80]
    DIRECTION INPUT ;
    USE SIGNAL ;
    ANTENNAGATEAREA 0.213000 ;
    PORT
      LAYER met1 ;
        RECT 382.295 167.990 382.595 168.270 ;
    END
  END wdata[80]
  PIN wdata[8]
    DIRECTION INPUT ;
    USE SIGNAL ;
    ANTENNAGATEAREA 0.213000 ;
    PORT
      LAYER met1 ;
        RECT 382.295 59.190 382.595 59.470 ;
    END
  END wdata[8]
  PIN wdata[9]
    DIRECTION INPUT ;
    USE SIGNAL ;
    ANTENNAGATEAREA 0.213000 ;
    PORT
      LAYER met2 ;
        RECT 292.650 0.000 292.930 0.280 ;
    END
  END wdata[9]
  PIN wen
    DIRECTION INPUT ;
    USE SIGNAL ;
    ANTENNAGATEAREA 0.213000 ;
    PORT
      LAYER met1 ;
        RECT 0.000 176.150 0.300 176.430 ;
    END
  END wen
  OBS
      LAYER nwell ;
        RECT 5.330 10.795 376.930 380.885 ;
      LAYER li1 ;
        RECT 5.520 10.795 376.740 380.885 ;
      LAYER met1 ;
        RECT 0.160 365.750 382.560 381.040 ;
        RECT 0.580 364.910 382.560 365.750 ;
        RECT 0.160 346.030 382.560 364.910 ;
        RECT 0.160 345.190 382.015 346.030 ;
        RECT 0.160 343.310 382.560 345.190 ;
        RECT 0.580 342.470 382.560 343.310 ;
        RECT 0.160 341.950 382.560 342.470 ;
        RECT 0.580 341.110 382.560 341.950 ;
        RECT 0.160 339.230 382.560 341.110 ;
        RECT 0.580 338.390 382.560 339.230 ;
        RECT 0.160 332.430 382.560 338.390 ;
        RECT 0.160 331.590 382.015 332.430 ;
        RECT 0.160 324.950 382.560 331.590 ;
        RECT 0.160 324.110 382.015 324.950 ;
        RECT 0.160 316.110 382.560 324.110 ;
        RECT 0.160 315.430 382.015 316.110 ;
        RECT 0.580 315.270 382.015 315.430 ;
        RECT 0.580 314.590 382.560 315.270 ;
        RECT 0.160 309.310 382.560 314.590 ;
        RECT 0.580 308.470 382.560 309.310 ;
        RECT 0.160 305.230 382.560 308.470 ;
        RECT 0.160 304.390 382.015 305.230 ;
        RECT 0.160 295.710 382.560 304.390 ;
        RECT 0.160 294.870 382.015 295.710 ;
        RECT 0.160 293.670 382.560 294.870 ;
        RECT 0.160 292.830 382.015 293.670 ;
        RECT 0.160 290.950 382.560 292.830 ;
        RECT 0.160 290.110 382.015 290.950 ;
        RECT 0.160 288.910 382.560 290.110 ;
        RECT 0.580 288.070 382.560 288.910 ;
        RECT 0.160 275.990 382.560 288.070 ;
        RECT 0.580 275.150 382.560 275.990 ;
        RECT 0.160 273.950 382.560 275.150 ;
        RECT 0.580 273.110 382.015 273.950 ;
        RECT 0.160 271.230 382.560 273.110 ;
        RECT 0.580 270.390 382.560 271.230 ;
        RECT 0.160 268.510 382.560 270.390 ;
        RECT 0.580 267.670 382.015 268.510 ;
        RECT 0.160 261.030 382.560 267.670 ;
        RECT 0.160 260.190 382.015 261.030 ;
        RECT 0.160 256.270 382.560 260.190 ;
        RECT 0.160 255.430 382.015 256.270 ;
        RECT 0.160 244.030 382.560 255.430 ;
        RECT 0.580 243.190 382.560 244.030 ;
        RECT 0.160 241.310 382.560 243.190 ;
        RECT 0.580 240.470 382.560 241.310 ;
        RECT 0.160 239.270 382.560 240.470 ;
        RECT 0.580 238.590 382.560 239.270 ;
        RECT 0.580 238.430 382.015 238.590 ;
        RECT 0.160 237.750 382.015 238.430 ;
        RECT 0.160 235.870 382.560 237.750 ;
        RECT 0.580 233.830 382.560 235.870 ;
        RECT 0.580 233.670 382.015 233.830 ;
        RECT 0.160 232.990 382.015 233.670 ;
        RECT 0.160 231.790 382.560 232.990 ;
        RECT 0.160 229.590 382.015 231.790 ;
        RECT 0.160 225.670 382.560 229.590 ;
        RECT 0.160 224.990 382.015 225.670 ;
        RECT 0.580 224.830 382.015 224.990 ;
        RECT 0.580 224.150 382.560 224.830 ;
        RECT 0.160 223.630 382.560 224.150 ;
        RECT 0.580 222.950 382.560 223.630 ;
        RECT 0.580 222.790 382.015 222.950 ;
        RECT 0.160 222.110 382.015 222.790 ;
        RECT 0.160 216.150 382.560 222.110 ;
        RECT 0.160 215.310 382.015 216.150 ;
        RECT 0.160 212.750 382.560 215.310 ;
        RECT 0.160 211.910 382.015 212.750 ;
        RECT 0.160 210.710 382.560 211.910 ;
        RECT 0.580 209.870 382.015 210.710 ;
        RECT 0.160 209.190 382.015 209.870 ;
        RECT 0.160 207.310 382.560 209.190 ;
        RECT 0.580 205.790 382.560 207.310 ;
        RECT 0.160 205.270 382.560 205.790 ;
        RECT 0.160 204.430 382.015 205.270 ;
        RECT 0.160 202.550 382.560 204.430 ;
        RECT 0.580 201.030 382.560 202.550 ;
        RECT 0.160 199.830 382.560 201.030 ;
        RECT 0.580 199.150 382.560 199.830 ;
        RECT 0.580 198.990 382.015 199.150 ;
        RECT 0.160 196.270 382.015 198.990 ;
        RECT 0.160 184.190 382.560 196.270 ;
        RECT 0.160 183.510 382.015 184.190 ;
        RECT 0.580 183.350 382.015 183.510 ;
        RECT 0.580 182.670 382.560 183.350 ;
        RECT 0.160 181.470 382.560 182.670 ;
        RECT 0.580 179.950 382.560 181.470 ;
        RECT 0.160 179.430 382.560 179.950 ;
        RECT 0.580 178.590 382.560 179.430 ;
        RECT 0.160 177.390 382.560 178.590 ;
        RECT 0.580 176.030 382.560 177.390 ;
        RECT 0.580 175.870 382.015 176.030 ;
        RECT 0.160 175.190 382.015 175.870 ;
        RECT 0.160 170.590 382.560 175.190 ;
        RECT 0.160 169.910 382.015 170.590 ;
        RECT 0.580 169.750 382.015 169.910 ;
        RECT 0.580 169.230 382.560 169.750 ;
        RECT 0.580 169.070 382.015 169.230 ;
        RECT 0.160 168.550 382.015 169.070 ;
        RECT 0.580 167.710 382.015 168.550 ;
        RECT 0.160 166.350 382.015 167.710 ;
        RECT 0.160 162.430 382.560 166.350 ;
        RECT 0.580 161.590 382.560 162.430 ;
        RECT 0.160 161.070 382.560 161.590 ;
        RECT 0.580 160.230 382.560 161.070 ;
        RECT 0.160 155.630 382.560 160.230 ;
        RECT 0.160 154.790 382.015 155.630 ;
        RECT 0.160 148.150 382.560 154.790 ;
        RECT 0.160 147.310 382.015 148.150 ;
        RECT 0.160 144.750 382.560 147.310 ;
        RECT 0.580 143.910 382.560 144.750 ;
        RECT 0.160 137.950 382.560 143.910 ;
        RECT 0.160 137.110 382.015 137.950 ;
        RECT 0.160 126.390 382.560 137.110 ;
        RECT 0.580 125.550 382.560 126.390 ;
        RECT 0.160 124.350 382.560 125.550 ;
        RECT 0.160 123.510 382.015 124.350 ;
        RECT 0.160 119.590 382.560 123.510 ;
        RECT 0.580 118.070 382.560 119.590 ;
        RECT 0.160 117.550 382.560 118.070 ;
        RECT 0.580 116.710 382.560 117.550 ;
        RECT 0.160 115.510 382.560 116.710 ;
        RECT 0.160 114.670 382.015 115.510 ;
        RECT 0.160 105.310 382.560 114.670 ;
        RECT 0.160 104.470 382.015 105.310 ;
        RECT 0.160 86.270 382.560 104.470 ;
        RECT 0.160 85.430 382.015 86.270 ;
        RECT 0.160 79.470 382.560 85.430 ;
        RECT 0.160 78.630 382.015 79.470 ;
        RECT 0.160 74.030 382.560 78.630 ;
        RECT 0.580 72.510 382.560 74.030 ;
        RECT 0.160 71.990 382.560 72.510 ;
        RECT 0.160 71.150 382.015 71.990 ;
        RECT 0.160 63.830 382.560 71.150 ;
        RECT 0.160 62.990 382.015 63.830 ;
        RECT 0.160 62.470 382.560 62.990 ;
        RECT 0.160 61.630 382.015 62.470 ;
        RECT 0.160 59.750 382.560 61.630 ;
        RECT 0.160 58.910 382.015 59.750 ;
        RECT 0.160 15.550 382.560 58.910 ;
        RECT 0.160 14.710 382.015 15.550 ;
        RECT 0.160 9.900 382.560 14.710 ;
      LAYER met2 ;
        RECT 1.020 392.755 79.850 393.245 ;
        RECT 80.690 392.755 97.330 393.245 ;
        RECT 98.170 392.755 101.010 393.245 ;
        RECT 101.850 392.755 102.850 393.245 ;
        RECT 103.690 392.755 109.290 393.245 ;
        RECT 110.130 392.755 110.210 393.245 ;
        RECT 111.050 392.755 133.210 393.245 ;
        RECT 134.050 392.755 134.130 393.245 ;
        RECT 134.970 392.755 135.050 393.245 ;
        RECT 135.890 392.755 151.610 393.245 ;
        RECT 152.450 392.755 155.290 393.245 ;
        RECT 156.130 392.755 157.130 393.245 ;
        RECT 157.970 392.755 158.050 393.245 ;
        RECT 158.890 392.755 168.170 393.245 ;
        RECT 169.010 392.755 178.290 393.245 ;
        RECT 179.130 392.755 182.890 393.245 ;
        RECT 183.730 392.755 193.010 393.245 ;
        RECT 193.850 392.755 194.850 393.245 ;
        RECT 195.690 392.755 195.770 393.245 ;
        RECT 196.610 392.755 196.690 393.245 ;
        RECT 197.530 392.755 211.410 393.245 ;
        RECT 212.250 392.755 219.690 393.245 ;
        RECT 220.530 392.755 220.610 393.245 ;
        RECT 221.450 392.755 231.650 393.245 ;
        RECT 232.490 392.755 239.010 393.245 ;
        RECT 239.850 392.755 239.930 393.245 ;
        RECT 240.770 392.755 251.890 393.245 ;
        RECT 252.730 392.755 257.410 393.245 ;
        RECT 258.250 392.755 269.370 393.245 ;
        RECT 270.210 392.755 270.290 393.245 ;
        RECT 271.130 392.755 279.490 393.245 ;
        RECT 280.330 392.755 282.250 393.245 ;
        RECT 283.090 392.755 288.690 393.245 ;
        RECT 289.530 392.755 312.610 393.245 ;
        RECT 313.450 392.755 381.700 393.245 ;
        RECT 1.020 0.560 381.700 392.755 ;
        RECT 1.020 0.070 66.050 0.560 ;
        RECT 66.890 0.070 66.970 0.560 ;
        RECT 67.810 0.070 81.690 0.560 ;
        RECT 82.530 0.070 83.530 0.560 ;
        RECT 84.370 0.070 84.450 0.560 ;
        RECT 85.290 0.070 93.650 0.560 ;
        RECT 94.490 0.070 94.570 0.560 ;
        RECT 95.410 0.070 95.490 0.560 ;
        RECT 96.330 0.070 108.370 0.560 ;
        RECT 109.210 0.070 119.410 0.560 ;
        RECT 120.250 0.070 123.090 0.560 ;
        RECT 123.930 0.070 126.770 0.560 ;
        RECT 127.610 0.070 134.130 0.560 ;
        RECT 134.970 0.070 138.730 0.560 ;
        RECT 139.570 0.070 142.410 0.560 ;
        RECT 143.250 0.070 157.130 0.560 ;
        RECT 157.970 0.070 160.810 0.560 ;
        RECT 161.650 0.070 161.730 0.560 ;
        RECT 162.570 0.070 162.650 0.560 ;
        RECT 163.490 0.070 163.570 0.560 ;
        RECT 164.410 0.070 173.690 0.560 ;
        RECT 174.530 0.070 193.010 0.560 ;
        RECT 193.850 0.070 193.930 0.560 ;
        RECT 194.770 0.070 194.850 0.560 ;
        RECT 195.690 0.070 195.770 0.560 ;
        RECT 196.610 0.070 196.690 0.560 ;
        RECT 197.530 0.070 197.610 0.560 ;
        RECT 198.450 0.070 198.530 0.560 ;
        RECT 199.370 0.070 199.450 0.560 ;
        RECT 200.290 0.070 226.130 0.560 ;
        RECT 226.970 0.070 227.050 0.560 ;
        RECT 227.890 0.070 227.970 0.560 ;
        RECT 228.810 0.070 235.330 0.560 ;
        RECT 236.170 0.070 236.250 0.560 ;
        RECT 237.090 0.070 237.170 0.560 ;
        RECT 238.010 0.070 255.570 0.560 ;
        RECT 256.410 0.070 256.490 0.560 ;
        RECT 257.330 0.070 257.410 0.560 ;
        RECT 258.250 0.070 259.250 0.560 ;
        RECT 260.090 0.070 267.530 0.560 ;
        RECT 268.370 0.070 268.450 0.560 ;
        RECT 269.290 0.070 283.170 0.560 ;
        RECT 284.010 0.070 285.930 0.560 ;
        RECT 286.770 0.070 292.370 0.560 ;
        RECT 293.210 0.070 381.700 0.560 ;
      LAYER met3 ;
        RECT 6.965 10.715 374.835 380.965 ;
      LAYER met4 ;
        RECT 26.975 13.095 174.240 379.945 ;
        RECT 176.640 13.095 177.540 379.945 ;
        RECT 179.940 13.095 327.840 379.945 ;
        RECT 330.240 13.095 331.140 379.945 ;
        RECT 333.540 13.095 362.610 379.945 ;
      LAYER met5 ;
        RECT 68.660 186.410 362.820 264.300 ;
        RECT 68.660 123.300 362.820 178.310 ;
  END
END fifo_basic_w81_d16
END LIBRARY

